VERSION 5.8 ;
BUSBITCHARS "[]" ;
DIVIDERCHAR "/" ;
UNITS
    DATABASE MICRONS 1000 ;
END UNITS

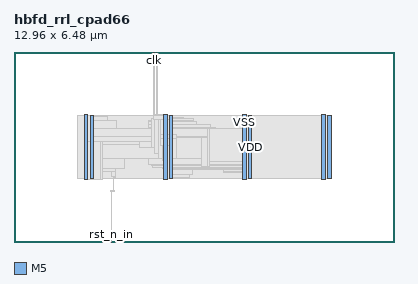
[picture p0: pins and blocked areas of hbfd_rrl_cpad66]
MACRO hbfd_rrl_cpad66
  FOREIGN hbfd_rrl_cpad66 0 0 ;
  CLASS BLOCK ;
  SIZE 12.96 BY 6.48 ;
  PIN clk
    DIRECTION INPUT ;
    USE SIGNAL ;
    PORT
      LAYER M5 ;
        RECT  4.752 6.396 4.776 6.48 ;
    END
  END clk
  PIN rst_n
    DIRECTION OUTPUT ;
    USE SIGNAL ;
    PORT
      LAYER M5 ;
        RECT  4.848 6.396 4.872 6.48 ;
    END
  END rst_n
  PIN rst_n_in
    DIRECTION INPUT ;
    USE SIGNAL ;
    PORT
      LAYER M5 ;
        RECT  3.312 0 3.336 0.084 ;
    END
  END rst_n_in
  PIN VDD
    DIRECTION INOUT ;
    USE POWER ;
    PORT
      LAYER M5 ;
        RECT  10.692 2.151 10.812 4.329 ;
        RECT  7.992 2.151 8.112 4.329 ;
        RECT  5.292 2.151 5.412 4.329 ;
        RECT  2.592 2.151 2.712 4.329 ;
    END
  END VDD
  PIN VSS
    DIRECTION INOUT ;
    USE GROUND ;
    PORT
      LAYER M5 ;
        RECT  10.5 2.137 10.62 4.343 ;
        RECT  7.8 2.137 7.92 4.343 ;
        RECT  5.1 2.137 5.22 4.343 ;
        RECT  2.4 2.137 2.52 4.343 ;
    END
  END VSS
  OBS
    LAYER RVTN ;
     RECT  2.16 2.16 10.8 2.295 ;
     RECT  2.16 2.565 10.8 2.835 ;
     RECT  2.16 3.105 10.8 3.375 ;
     RECT  2.16 3.645 10.8 3.915 ;
     RECT  2.16 4.185 10.8 4.32 ;
    LAYER RVTP ;
     RECT  2.16 2.295 10.8 2.565 ;
     RECT  2.16 2.835 10.8 3.105 ;
     RECT  2.16 3.375 10.8 3.645 ;
     RECT  2.16 3.915 10.8 4.185 ;
    LAYER M1 ;
     RECT  2.16 2.151 10.8 4.329 ;
    LAYER M2 ;
     RECT  2.16 2.151 10.8 4.329 ;
     RECT  10.8 2.421 10.812 4.059 ;
    LAYER M3 ;
     RECT  3.384 1.723 3.402 2.191 ;
     RECT  5.115 2.143 5.205 2.191 ;
     RECT  3.384 2.191 3.474 2.227 ;
     RECT  5.115 2.191 5.994 2.299 ;
     RECT  7.815 2.143 7.905 2.371 ;
     RECT  2.415 2.143 2.505 2.413 ;
     RECT  3.312 2.227 3.474 2.413 ;
     RECT  7.128 2.371 7.905 2.413 ;
     RECT  10.515 2.143 10.605 2.413 ;
     RECT  5.115 2.299 6.102 2.461 ;
     RECT  7.128 2.413 8.097 2.461 ;
     RECT  2.415 2.413 3.474 2.497 ;
     RECT  5.115 2.461 8.097 2.497 ;
     RECT  5.076 2.497 8.097 2.533 ;
     RECT  4.716 2.533 8.097 2.605 ;
     RECT  4.68 2.605 8.097 2.641 ;
     RECT  2.415 2.497 3.762 2.839 ;
     RECT  4.572 2.641 8.097 2.839 ;
     RECT  2.415 2.839 8.097 3.415 ;
     RECT  2.412 3.415 8.097 3.605 ;
     RECT  2.415 3.605 8.097 3.875 ;
     RECT  4.572 3.875 6.858 3.911 ;
     RECT  4.572 3.911 6.714 4.019 ;
     RECT  7.815 3.875 8.097 4.067 ;
     RECT  10.515 2.413 10.797 4.067 ;
     RECT  4.572 4.019 6.21 4.109 ;
     RECT  2.415 3.875 3.51 4.145 ;
     RECT  4.572 4.109 6.138 4.145 ;
     RECT  4.752 4.145 6.138 4.205 ;
     RECT  4.86 4.205 6.138 4.217 ;
     RECT  4.86 4.217 5.778 4.253 ;
     RECT  2.415 4.145 3.186 4.289 ;
     RECT  2.415 4.289 2.505 4.337 ;
     RECT  4.86 4.253 5.205 4.337 ;
     RECT  7.815 4.067 7.905 4.337 ;
     RECT  10.515 4.067 10.605 4.337 ;
     RECT  4.86 4.337 4.878 6.365 ;
    LAYER M4 ;
     RECT  2.408 2.148 2.512 4.332 ;
     RECT  2.512 2.148 2.704 4.062 ;
     RECT  2.704 2.148 3.004 3.432 ;
     RECT  3.301 1.728 3.413 1.752 ;
     RECT  3.004 3.312 4.273 3.432 ;
     RECT  4.273 3.216 4.7 3.432 ;
     RECT  4.7 3.216 4.777 4.2 ;
     RECT  4.805 6.336 4.889 6.36 ;
     RECT  4.777 3.024 4.921 4.2 ;
     RECT  4.921 2.832 5.065 4.2 ;
     RECT  5.065 2.784 5.108 4.2 ;
     RECT  5.108 2.148 5.212 4.332 ;
     RECT  5.212 2.418 5.404 4.062 ;
     RECT  5.404 2.832 5.555 3.672 ;
     RECT  5.555 2.832 6.397 3.576 ;
     RECT  6.397 2.592 6.613 3.576 ;
     RECT  6.613 2.592 6.653 3.864 ;
     RECT  6.653 2.736 7.808 3.864 ;
     RECT  7.808 2.148 7.912 4.332 ;
     RECT  7.912 2.418 8.104 4.062 ;
     RECT  10.508 2.148 10.612 4.332 ;
     RECT  10.612 2.418 10.804 4.062 ;
    LAYER M5 ;
     RECT  3.312 0.016 3.336 1.763 ;
     RECT  5.1 2.137 5.22 2.151 ;
     RECT  7.8 2.137 7.92 2.151 ;
     RECT  10.5 2.137 10.62 2.151 ;
     RECT  5.1 2.151 5.412 3.301 ;
     RECT  2.4 2.137 2.952 3.443 ;
     RECT  4.992 3.301 5.412 3.541 ;
     RECT  4.992 3.541 5.544 3.683 ;
     RECT  4.992 3.683 5.412 4.165 ;
     RECT  2.4 3.443 2.712 4.329 ;
     RECT  4.752 4.165 5.412 4.329 ;
     RECT  7.8 2.151 8.112 4.329 ;
     RECT  10.5 2.151 10.812 4.329 ;
     RECT  2.4 4.329 2.52 4.343 ;
     RECT  4.752 4.329 5.22 4.343 ;
     RECT  7.8 4.329 7.92 4.343 ;
     RECT  10.5 4.329 10.62 4.343 ;
     RECT  4.752 4.343 4.776 6.325 ;
     RECT  4.752 6.325 4.872 6.416 ;
  END
END hbfd_rrl_cpad66
END LIBRARY
